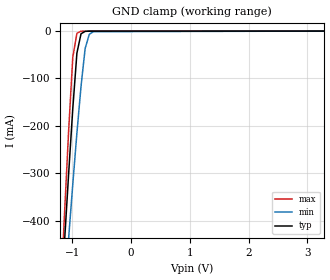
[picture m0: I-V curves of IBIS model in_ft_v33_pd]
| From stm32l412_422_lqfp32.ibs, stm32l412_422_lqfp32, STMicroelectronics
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|   Model in_ft_v33_pd
[Model]  in_ft_v33_pd
Model_type Input
Polarity   Non-Inverting
Vinl =   0.990000V
Vinh =   2.310000V
C_comp   0.872570pF   0.859810pF   0.888860pF
[Temperature Range]   25.000000   0.140000k   -40.000000
[Pullup Reference]   3.300000V   2.700000V   3.600000V
[Pulldown Reference]   0.0V   0.0V   0.0V
[POWER Clamp Reference]   3.300000V   2.700000V   3.600000V
[GND Clamp Reference]   0.0V   0.0V   0.0V
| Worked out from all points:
|   GND clamp passes 1 mA (typ) near -0.79 V on its own axis
[GND_clamp]
|Voltage   I(typ)   I(min)   I(max)
-3.3V     -6.646A    -5.438A    -8.156A
-1.2V     -590.7mA   -670.1mA   -565.1mA
-1.13V    -443.4mA   -552mA     -383.5mA
-1.06V    -299.9mA   -436mA     -208.7mA
-990mV    -163.6mA   -323mA     -55.26mA
-920mV    -46.38mA   -215.2mA   -4.579mA
-850mV    -5.609mA   -116.8mA   -194uA
-780mV    -487.7uA   -36.74mA   -22.88uA
-710mV    -52.94uA   -6.807mA   -15.68uA
-640mV    -19.36uA   -1.182mA   -13.97uA
3.28V     87.11uA    89.08uA    71.58uA
[POWER_clamp]
|Voltage   I(typ)   I(min)   I(max)
-3.28V    0A         0A         0A
0V        0A         0A         0A
